VERSION 5.8 ;
BUSBITCHARS "[]" ;
DIVIDERCHAR "/" ;
CLEARANCEMEASURE EUCLIDEAN ;

SITE coresite_DH_P
    SIZE 0.0450 BY 0.2880 ;
    CLASS CORE ;
    SYMMETRY X Y ;
END coresite_DH_P

SITE coresite_DH_N
    SIZE 0.0450 BY 0.2880 ;
    CLASS CORE ;
    SYMMETRY X Y ;
END coresite_DH_N

SITE coresite
    SIZE 0.0450 BY 0.1440 ;
    CLASS CORE ;
    SYMMETRY X Y ;
END coresite

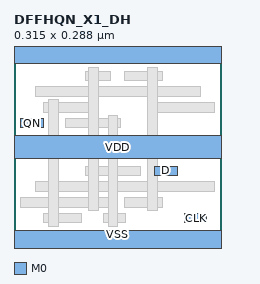
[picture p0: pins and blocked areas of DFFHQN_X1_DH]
MACRO DFFHQN_X1_DH
  CLASS CORE ;
  ORIGIN 0 0 ;
  FOREIGN DFFHQN_X1_DH 0 0 ;
  SIZE 0.3150 BY 0.2880 ;
  SYMMETRY X Y ;
  SITE coresite_DH_N ;
  PIN CLK
    DIRECTION INPUT ;
    USE SIGNAL ;
    PORT
      LAYER M0 ;
        RECT 0.2580 0.0430 0.2925 0.0290 ;
    END
  END CLK
  PIN D
    DIRECTION INPUT ;
    USE SIGNAL ;
    PORT
      LAYER M0 ;
        RECT 0.2130 0.1150 0.2475 0.1010 ;
    END
  END D
  PIN QN
    DIRECTION OUTPUT ;
    USE SIGNAL ;
    PORT
      LAYER M0 ;
        RECT 0.0105 0.1870 0.0450 0.1730 ;
    END
  END QN
  PIN VDD
    DIRECTION INOUT ;
    USE POWER ;
    SHAPE ABUTMENT ;
    PORT
      LAYER M0 ;
        RECT 0.0000 0.1260 0.3150 0.1620 ;
    END
  END VDD
  PIN VSS
    DIRECTION INOUT ;
    USE GROUND ;
    SHAPE ABUTMENT ;
    PORT
      LAYER M0 ;
        RECT 0.0000 -0.0180 0.3150 0.0180 ;
        RECT 0.0000 0.2700 0.3150 0.3060 ;
    END
  END VSS
  OBS
      LAYER V0 ;
        RECT 0.1430 0.0290 0.1570 0.0430 ;
        RECT 0.1430 0.1730 0.1570 0.1870 ;
        RECT 0.2030 0.0770 0.2170 0.0910 ;
        RECT 0.2030 0.0530 0.2170 0.0670 ;
        RECT 0.2030 0.2450 0.2170 0.2590 ;
        RECT 0.0530 0.0290 0.0670 0.0430 ;
        RECT 0.0530 0.1970 0.0670 0.2110 ;
        RECT 0.1130 0.1010 0.1270 0.1150 ;
        RECT 0.1130 0.0530 0.1270 0.0670 ;
        RECT 0.1130 0.2450 0.1270 0.2590 ;
      LAYER M0 ;
        RECT 0.0450 0.0290 0.1020 0.0430 ;
        RECT 0.1350 0.0290 0.1695 0.0430 ;
        RECT 0.0105 0.0530 0.1470 0.0670 ;
        RECT 0.1680 0.0530 0.2250 0.0670 ;
        RECT 0.0330 0.0770 0.3045 0.0910 ;
        RECT 0.1080 0.1010 0.1920 0.1150 ;
        RECT 0.0780 0.1730 0.1620 0.1870 ;
        RECT 0.0450 0.1970 0.1245 0.2110 ;
        RECT 0.2130 0.1970 0.3045 0.2110 ;
        RECT 0.0330 0.2210 0.2820 0.2350 ;
        RECT 0.1080 0.2450 0.1470 0.2590 ;
        RECT 0.1680 0.2450 0.2250 0.2590 ;
      LAYER M1 ;
        RECT 0.1425 0.1920 0.1575 0.0240 ;
        RECT 0.0525 0.2160 0.0675 0.0240 ;
        RECT 0.1125 0.2640 0.1275 0.0480 ;
        RECT 0.2025 0.2640 0.2175 0.0480 ;
  END
END DFFHQN_X1_DH

END LIBRARY
